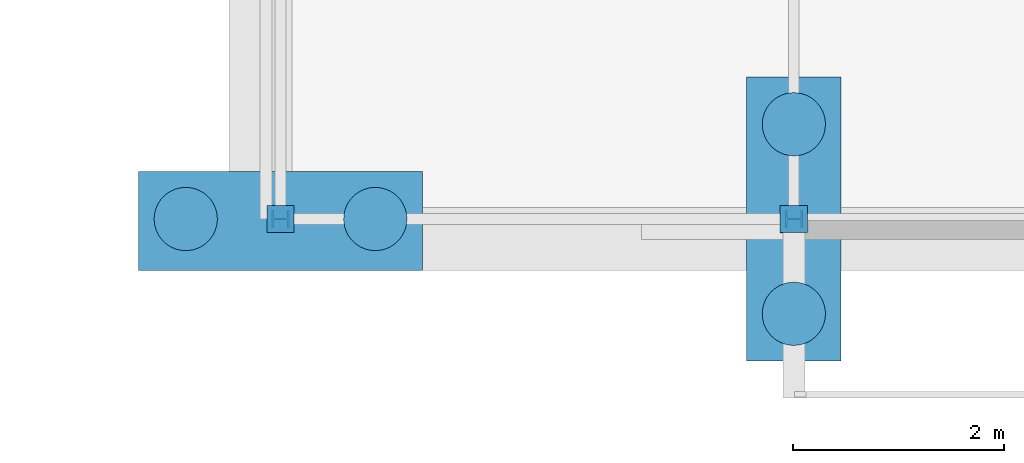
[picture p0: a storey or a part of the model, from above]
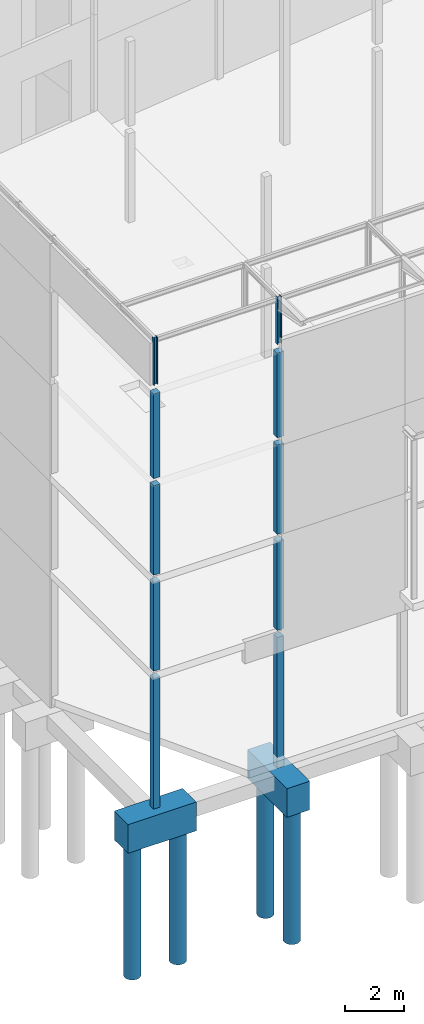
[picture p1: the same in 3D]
Properties of the parts of a building model (IFC2X3)

# File
Description: ViewDefinition[CoordinationView_V2.0]
File name: Struc.ifc
Time: 2015-04-22T10:52:00
Author: TEKLAAD\alco
Organization: Structural Designer
Written by: IFC Database Version:Work
Made in: Tekla Structures 21.0, IFC Export Version: 4.0.0.0 Mar 10 2015

# IfcSite, Undefined
RefElevation: 0 mm

# IfcBuildingStorey, Undefined
In: Undefined
Elevation: 0 mm

# IfcBeam: 1200*1000 (3)
In: Undefined
Description: 1200*1000; Material: CONCRETE/C30/37
Tekla Commun - Etage d'implantation: Fondation; Phase: 102; Classe: 4; Matériau: C30/37; Profil: 1200*1000; Nom: LONGRINE
Pset_BeamCommon - LoadBearing: yes
Name | Repère de pièce = Reference | Repère d'assemblage
2 x LONGRINE | Béton_SO-15 | SO11
LONGRINE | LO40 | LO40

# IfcBeam: 1200*900 (4)
In: Undefined
Description: 1200*900; Material: CONCRETE/C30/37
Tekla Commun - Etage d'implantation: Fondation; Phase: 102; Classe: 4; Matériau: C30/37; Profil: 1200*900; Nom: LONGRINE
Pset_BeamCommon - LoadBearing: yes
Name | Repère de pièce = Reference | Repère d'assemblage
2 x LONGRINE | Béton_SO-14 | SO11
LONGRINE | LO39 | LO39
LONGRINE | LO38 | LO38

# IfcBeam: 600*200, LONGRINE
In: Undefined
Description: 600*200; Material: CONCRETE/C30/37
Tekla Commun - Etage d'implantation: Fondation; Repère de pièce: LO41; Repère d'assemblage: LO41; Phase: 102; Classe: 4; Matériau: C30/37; Profil: 600*200; Nom: LONGRINE
Pset_BeamCommon - LoadBearing: yes; Reference: LO41

# IfcBeam: 600*400 (4)
In: Undefined
Description: 600*400; Material: CONCRETE/C30/37
Tekla Commun - Etage d'implantation: Fondation; Phase: 102; Classe: 4; Matériau: C30/37; Profil: 600*400; Nom: LONGRINE
Pset_BeamCommon - LoadBearing: yes
Name | Repère de pièce = Repère d'assemblage = Reference
LONGRINE | LO42
LONGRINE | LO43
2 x LONGRINE | LO44

# IfcBeam: 600*600 (49)
In: Undefined
Description: 600*600; Material: CONCRETE/C30/37
Tekla Commun - Etage d'implantation: Fondation; Phase: 102; Classe: 4; Matériau: C30/37; Profil: 600*600; Nom: LONGRINE
Pset_BeamCommon - LoadBearing: yes
Name | Repère de pièce = Repère d'assemblage = Reference
2 x LONGRINE | LO36
LONGRINE | LO37
2 x LONGRINE | LO32
2 x LONGRINE | LO35
2 x LONGRINE | LO34
LONGRINE | LO33
LONGRINE | LO31
2 x LONGRINE | LO26
LONGRINE | LO28
LONGRINE | LO27
LONGRINE | LO25
LONGRINE | LO24
LONGRINE | LO23
LONGRINE | LO22
LONGRINE | LO21
LONGRINE | LO1
LONGRINE | LO2
LONGRINE | LO19
LONGRINE | LO18
LONGRINE | LO17
LONGRINE | LO16
LONGRINE | LO15
LONGRINE | LO13
LONGRINE | LO12
LONGRINE | LO11
LONGRINE | LO10
3 x LONGRINE | LO9
LONGRINE | LO8
LONGRINE | LO7
LONGRINE | LO6
9 x LONGRINE | LO4
2 x LONGRINE | LO5
LONGRINE | LO3

# IfcBeam: 600*800 (3)
In: Undefined
Description: 600*800; Material: CONCRETE/C30/37
Tekla Commun - Etage d'implantation: Fondation; Phase: 102; Classe: 4; Matériau: C30/37; Profil: 600*800; Nom: LONGRINE
Pset_BeamCommon - LoadBearing: yes
Name | Repère de pièce = Repère d'assemblage = Reference
LONGRINE | LO30
LONGRINE | LO29
LONGRINE | LO20

# IfcBeam: 850*600, LONGRINE
In: Undefined
Description: 850*600; Material: CONCRETE/C30/37
Tekla Commun - Etage d'implantation: Fondation; Repère de pièce: LO14; Repère d'assemblage: LO14; Phase: 102; Classe: 4; Matériau: C30/37; Profil: 850*600; Nom: LONGRINE
Pset_BeamCommon - LoadBearing: yes; Reference: LO14

# IfcBeam: HEB200 (10)
In: Undefined
Description: HEB200; Material: STEEL/S275JR
Tekla Commun - Phase: 701; Classe: 3; Matériau: S275JR; Profil: HEB200; Nom: POUTRE
Pset_BeamCommon - LoadBearing: yes
Name | Repère de pièce = Repère d'assemblage = Reference
POUTRE | PO76
POUTRE | PO75
POUTRE | PO74
POUTRE | PO73
POUTRE | PO72
POUTRE | PO71
POUTRE | PO70
POUTRE | PO69
POUTRE | PO68
POUTRE | PO67

# IfcBeam: IPE200 (107)
In: Undefined
Description: IPE200; Material: STEEL/S275JR
Tekla Commun - Phase: 702; Classe: 3; Matériau: S275JR; Profil: IPE200; Nom: POUTRE
Pset_BeamCommon - LoadBearing: yes
Name | Repère de pièce = Repère d'assemblage = Reference
6 x POUTRE | PO62
2 x POUTRE | PO66
4 x POUTRE | PO61
POUTRE | PO65
2 x POUTRE | PO64
POUTRE | PO63
POUTRE | PO28
POUTRE | PO60
POUTRE | PO59
POUTRE | PO58
6 x POUTRE | PO40
POUTRE | PO57
4 x POUTRE | PO52
POUTRE | PO56
2 x POUTRE | PO55
POUTRE | PO54
POUTRE | PO53
21 x POUTRE | PO41
POUTRE | PO26
POUTRE | PO25
POUTRE | PO51
2 x POUTRE | PO49
POUTRE | PO50
POUTRE | PO48
POUTRE | PO47
POUTRE | PO46
POUTRE | PO45
POUTRE | PO24
POUTRE | PO27
2 x POUTRE | PO44
20 x POUTRE | PO42
4 x POUTRE | PO43
POUTRE | PO39
POUTRE | PO38
POUTRE | PO37
POUTRE | PO36
POUTRE | PO35
POUTRE | PO34
2 x POUTRE | PO33
POUTRE | PO32
POUTRE | PO31
POUTRE | PO30
POUTRE | PO29

# IfcBeam: IPE300, POUTRE
In: Undefined
Description: IPE300; Material: STEEL/S275JR
Tekla Commun - Repère de pièce: PO1; Repère d'assemblage: PO1; Phase: 702; Classe: 3; Matériau: S275JR; Profil: IPE300; Nom: POUTRE
Pset_BeamCommon - LoadBearing: yes; Reference: PO1

# IfcBeam: IPE400 (6)
In: Undefined
Description: IPE400; Material: STEEL/S275JR
Tekla Commun - Phase: 702; Classe: 3; Matériau: S275JR; Profil: IPE400; Nom: POUTRE
Pset_BeamCommon - LoadBearing: yes
Name | Repère de pièce = Repère d'assemblage = Reference
POUTRE | PO7
POUTRE | PO6
POUTRE | PO3
POUTRE | PO5
POUTRE | PO2
POUTRE | PO4

# IfcBeam: PHI533-200-10-14*210-14*210 (23)
In: Undefined
Description: PHI533-200-10-14*210-14*210; Material: STEEL/S275JR
Tekla Commun - Phase: 702; Classe: 3; Matériau: S275JR; Profil: PHI533-200-10-14*210-14*210; Nom: POUTRE
Pset_BeamCommon - LoadBearing: yes
Name | Repère de pièce = Repère d'assemblage = Reference
20 x POUTRE | PO11
POUTRE | PO10
POUTRE | PO9
POUTRE | PO8

# IfcBeam: UPE120 (24)
In: Undefined
Description: UPE120; Material: STEEL/S275JR
Tekla Commun - Classe: 3; Matériau: S275JR; Profil: UPE120; Nom: POUTRE
Pset_BeamCommon - LoadBearing: yes
Name | Repère de pièce = Repère d'assemblage = Reference | Phase
2 x POUTRE | PO22 | 702
POUTRE | PO15 | 702
POUTRE | PO23 | 702
POUTRE | PO14 | 702
3 x POUTRE | PO20 | 702
POUTRE | PO13 | 702
POUTRE | PO21 | 702
POUTRE | PO12 | 702
POUTRE | PO19 | 601
POUTRE | PO18 | 702
9 x POUTRE | PO16 | 702
2 x POUTRE | PO17 | 702

# IfcBeam: UPE200 (18)
In: Undefined
Description: UPE200; Material: STEEL/S275JR
Tekla Commun - Phase: 701; Classe: 3; Matériau: S275JR; Profil: UPE200; Nom: POUTRE
Pset_BeamCommon - LoadBearing: yes
Name | Repère de pièce = Repère d'assemblage = Reference
2 x POUTRE | PO81
7 x POUTRE | PO80
2 x POUTRE | PO78
7 x POUTRE | PO77

# IfcColumn: 1200*1200 (4)
In: Undefined
Description: 1200*1200; Material: CONCRETE/C30/37
Tekla Commun - Etage d'implantation: Fondation; Repère de pièce: SO9; Repère d'assemblage: SO9; Phase: 102; Classe: 4; Matériau: C30/37; Profil: 1200*1200; Nom: SEMELLE
Pset_ColumnCommon - LoadBearing: yes; Reference: SO9

# IfcColumn: 1200*1350 (2)
In: Undefined
Description: 1200*1350; Material: CONCRETE/C30/37
Tekla Commun - Etage d'implantation: Fondation; Repère de pièce: Béton_SO-113; Repère d'assemblage: SO11; Phase: 102; Classe: 4; Matériau: C30/37; Profil: 1200*1350; Nom: SEMELLE
Pset_ColumnCommon - LoadBearing: yes; Reference: Béton_SO-113

# IfcColumn: 1200*2459, SEMELLE
In: Undefined
Description: 1200*2459; Material: CONCRETE/C30/37
Tekla Commun - Etage d'implantation: Fondation; Repère de pièce: SO8; Repère d'assemblage: SO8; Phase: 102; Classe: 4; Matériau: C30/37; Profil: 1200*2459; Nom: SEMELLE
Pset_ColumnCommon - LoadBearing: yes; Reference: SO8

# IfcColumn: 1200*2460 (7)
In: Undefined
Description: 1200*2460; Material: CONCRETE/C30/37
Tekla Commun - Etage d'implantation: Fondation; Phase: 102; Classe: 4; Matériau: C30/37; Profil: 1200*2460; Nom: SEMELLE
Pset_ColumnCommon - LoadBearing: yes
Name | Repère de pièce = Repère d'assemblage = Reference
6 x SEMELLE | SO7
SEMELLE | SO7(?)

# IfcColumn: 1200*2700, SEMELLE
In: Undefined
Description: 1200*2700; Material: CONCRETE/C30/37
Tekla Commun - Etage d'implantation: Fondation; Repère de pièce: SO13; Repère d'assemblage: SO13; Phase: 102; Classe: 4; Matériau: C30/37; Profil: 1200*2700; Nom: SEMELLE
Pset_ColumnCommon - LoadBearing: yes; Reference: SO13

# IfcColumn: 1200*4695, SEMELLE
In: Undefined
Description: 1200*4695; Material: CONCRETE/C30/37
Tekla Commun - Etage d'implantation: Fondation; Repère de pièce: SO10; Repère d'assemblage: SO10; Phase: 102; Classe: 4; Matériau: C30/37; Profil: 1200*4695; Nom: SEMELLE
Pset_ColumnCommon - LoadBearing: yes; Reference: SO10

# IfcColumn: 1200*4775, SEMELLE
In: Undefined
Description: 1200*4775; Material: CONCRETE/C30/37
Tekla Commun - Etage d'implantation: Fondation; Repère de pièce: SO12; Repère d'assemblage: SO12; Phase: 102; Classe: 4; Matériau: C30/37; Profil: 1200*4775; Nom: SEMELLE
Pset_ColumnCommon - LoadBearing: yes; Reference: SO12

# IfcColumn: 1500*1500, SEMELLE
In: Undefined
Description: 1500*1500; Material: CONCRETE/C30/37
Tekla Commun - Etage d'implantation: Fondation; Repère de pièce: SO5; Repère d'assemblage: SO5; Phase: 102; Classe: 4; Matériau: C30/37; Profil: 1500*1500; Nom: SEMELLE
Pset_ColumnCommon - LoadBearing: yes; Reference: SO5

# IfcColumn: 260*260 (185)
In: Undefined
Description: 260*260; Material: CONCRETE/C25/30
Tekla Commun - Classe: 13; Matériau: C25/30; Profil: 260*260; Nom: POTEAU
Pset_ColumnCommon - LoadBearing: yes
Name | Etage d'implantation | Repère de pièce = Repère d'assemblage = Reference | Phase
49 x POTEAU | 3ème | Pt7 | 502
36 x POTEAU | 2ème | Pt11 | 402
36 x POTEAU | 1er | Pt4 | 302
47 x POTEAU | Rdc | Pt1 | 202
2 x POTEAU | 1er | Pt3 | 302
2 x POTEAU | 2ème | Pt10 | 402
11 x POTEAU | 2ème | Pt5 | 302
POTEAU | Rdc | Pt6 | 202
POTEAU | Rdc | Pt2 | 202

# IfcColumn: 2700*2700, SEMELLE
In: Undefined
Description: 2700*2700; Material: CONCRETE/C30/37
Tekla Commun - Etage d'implantation: Fondation; Repère de pièce: SO4; Repère d'assemblage: SO4; Phase: 102; Classe: 4; Matériau: C30/37; Profil: 2700*2700; Nom: SEMELLE
Pset_ColumnCommon - LoadBearing: yes; Reference: SO4

# IfcColumn: 2700*900 (32)
In: Undefined
Description: 2700*900; Material: CONCRETE/C30/37
Tekla Commun - Etage d'implantation: Fondation; Phase: 102; Classe: 4; Matériau: C30/37; Profil: 2700*900; Nom: SEMELLE
Pset_ColumnCommon - LoadBearing: yes
Name | Repère de pièce = Repère d'assemblage = Reference
31 x SEMELLE | SO2
SEMELLE | SO2(?)

# IfcColumn: 2700*940 (2)
In: Undefined
Description: 2700*940; Material: CONCRETE/C30/37
Tekla Commun - Etage d'implantation: Fondation; Repère de pièce: SO1; Repère d'assemblage: SO1; Phase: 102; Classe: 4; Matériau: C30/37; Profil: 2700*940; Nom: SEMELLE
Pset_ColumnCommon - LoadBearing: yes; Reference: SO1

# IfcColumn: 3000*1500, SEMELLE
In: Undefined
Description: 3000*1500; Material: CONCRETE/C30/37
Tekla Commun - Etage d'implantation: Fondation; Repère de pièce: SO6; Repère d'assemblage: SO6; Phase: 102; Classe: 4; Matériau: C30/37; Profil: 3000*1500; Nom: SEMELLE
Pset_ColumnCommon - LoadBearing: yes; Reference: SO6

# IfcColumn: 900*900 (8)
In: Undefined
Description: 900*900; Material: CONCRETE/C30/37
Tekla Commun - Etage d'implantation: Fondation; Phase: 102; Classe: 4; Matériau: C30/37; Profil: 900*900; Nom: SEMELLE
Pset_ColumnCommon - LoadBearing: yes
Name | Repère de pièce = Repère d'assemblage = Reference
7 x SEMELLE | SO3
SEMELLE | SO14

# IfcColumn: D500 (2)
In: Undefined
Description: D500; Material: CONCRETE/C25/30
Tekla Commun - Classe: 13; Matériau: C25/30; Profil: D500; Nom: POTEAU
Pset_ColumnCommon - LoadBearing: yes
Name | Etage d'implantation | Repère de pièce = Repère d'assemblage = Reference | Phase
POTEAU | 2ème | Pt9 | 402
POTEAU | Rdc | Pt8 | 202

# IfcColumn: D600 (135)
In: Undefined
Description: D600; Material: CONCRETE/C25/30
Tekla Commun - Etage d'implantation: Fondation; Phase: 101; Classe: 13; Matériau: C25/30; Profil: D600; Nom: PIEU
Pset_ColumnCommon - LoadBearing: yes
Name | Repère de pièce = Repère d'assemblage = Reference
62 x PIEU | PI1
11 x PIEU | PI4
55 x PIEU | PI2
PIEU | PI3
2 x PIEU | PI2(?)
4 x PIEU | PI5

# IfcColumn: HEB160 (84)
In: Undefined
Description: HEB160; Material: STEEL/S275JR
Tekla Commun - Phase: 702; Classe: 6; Matériau: S275JR; Profil: HEB160; Nom: POTEAU
Pset_ColumnCommon - LoadBearing: yes
Name | Repère de pièce = Repère d'assemblage = Reference
75 x POTEAU | PT1
9 x POTEAU | PT2

# IfcColumn: UPE200 (10)
In: Undefined
Description: UPE200; Material: STEEL/S275JR
Tekla Commun - Repère de pièce: PO79; Repère d'assemblage: PO79; Phase: 701; Classe: 3; Matériau: S275JR; Profil: UPE200; Nom: POUTRE
Pset_ColumnCommon - LoadBearing: yes; Reference: PO79

# IfcSlab: 150*8179, DALLE
In: Undefined
Description: 150*8179; PredefinedType: FLOOR; Material: CONCRETE/C25/30 150 mm
Tekla Commun - Etage d'implantation: 4ème; Repère de pièce: DA1; Repère d'assemblage: DA1; Phase: 601; Classe: 5; Matériau: C25/30; Profil: 150*8179; Nom: DALLE
Pset_SlabCommon - LoadBearing: yes; Reference: DA1

# IfcSlab: 230*1916, PALIER
In: Undefined
Description: 230*1916; PredefinedType: FLOOR; Material: CONCRETE/C30/37 230 mm
Tekla Commun - Etage d'implantation: Rdc; Repère de pièce: PAL2; Repère d'assemblage: PAL2; Phase: 201; Classe: 11; Matériau: C30/37; Profil: 230*1916; Nom: PALIER
Pset_SlabCommon - LoadBearing: yes; Reference: PAL2

# IfcSlab: 300*1020 (4)
In: Undefined
Description: 300*1020; PredefinedType: FLOOR; Material: CONCRETE/C30/37 300 mm
Tekla Commun - Repère de pièce: DA16; Repère d'assemblage: DA16; Classe: 8; Matériau: C30/37; Profil: 300*1020; Nom: DALLE
Pset_SlabCommon - LoadBearing: yes; Reference: DA16
Name | Etage d'implantation | Phase
DALLE | 3ème | 501
DALLE | 2ème | 401
DALLE | 1er | 301
DALLE | Rdc | 201

# IfcSlab: 300*1251 (4)
In: Undefined
Description: 300*1251; PredefinedType: FLOOR; Material: CONCRETE/C30/37 300 mm
Tekla Commun - Classe: 8; Matériau: C30/37; Profil: 300*1251; Nom: DALLE
Pset_SlabCommon - LoadBearing: yes
Name | Etage d'implantation | Repère de pièce = Repère d'assemblage = Reference | Phase
DALLE | 3ème | DA25 | 501
DALLE | 2ème | DA25 | 401
DALLE | 1er | DA25 | 301
DALLE | Rdc | DA21 | 201

# IfcSlab: 300*1325 (4)
In: Undefined
Description: 300*1325; PredefinedType: FLOOR; Material: CONCRETE/C30/37 300 mm
Tekla Commun - Classe: 8; Matériau: C30/37; Profil: 300*1325; Nom: DALLE
Pset_SlabCommon - LoadBearing: yes
Name | Etage d'implantation | Repère de pièce = Repère d'assemblage = Reference | Phase
DALLE | 3ème | DA24 | 501
DALLE | 2ème | DA24 | 401
DALLE | 1er | DA24 | 301
DALLE | Rdc | DA22 | 201

# IfcSlab: 300*1374 (4)
In: Undefined
Description: 300*1374; PredefinedType: FLOOR; Material: CONCRETE/C30/37 300 mm
Tekla Commun - Repère de pièce: DA15; Repère d'assemblage: DA15; Classe: 8; Matériau: C30/37; Profil: 300*1374; Nom: DALLE
Pset_SlabCommon - LoadBearing: yes; Reference: DA15
Name | Etage d'implantation | Phase
DALLE | 3ème | 501
DALLE | 2ème | 401
DALLE | 1er | 301
DALLE | Rdc | 201

# IfcSlab: 300*13791, DALLE
In: Undefined
Description: 300*13791; PredefinedType: FLOOR; Material: CONCRETE/C30/37 300 mm
Tekla Commun - Etage d'implantation: 2ème; Repère de pièce: DA31; Repère d'assemblage: DA31; Phase: 401; Classe: 8; Matériau: C30/37; Profil: 300*13791; Nom: DALLE
Pset_SlabCommon - LoadBearing: yes; Reference: DA31

# IfcSlab: 300*1430 (8)
In: Undefined
Description: 300*1430; PredefinedType: FLOOR; Material: CONCRETE/C30/37 300 mm
Tekla Commun - Classe: 8; Matériau: C30/37; Profil: 300*1430; Nom: DALLE
Pset_SlabCommon - LoadBearing: yes
Name | Etage d'implantation | Repère de pièce = Repère d'assemblage = Reference | Phase
DALLE | 3ème | DA18 | 501
DALLE | 3ème | DA17 | 501
DALLE | 2ème | DA18 | 401
DALLE | 2ème | DA17 | 401
DALLE | 1er | DA18 | 301
DALLE | 1er | DA17 | 301
DALLE | Rdc | DA18 | 201
DALLE | Rdc | DA17 | 201

# IfcSlab: 300*1578, DALLE
In: Undefined
Description: 300*1578; PredefinedType: FLOOR; Material: CONCRETE/C30/37 300 mm
Tekla Commun - Etage d'implantation: Rdc; Repère de pièce: DA3; Repère d'assemblage: DA3; Phase: 201; Classe: 8; Matériau: C30/37; Profil: 300*1578; Nom: DALLE
Pset_SlabCommon - LoadBearing: yes; Reference: DA3

# IfcSlab: 300*1604 (4)
In: Undefined
Description: 300*1604; PredefinedType: FLOOR; Material: CONCRETE/C30/37 300 mm
Tekla Commun - Repère de pièce: DA14; Repère d'assemblage: DA14; Classe: 8; Matériau: C30/37; Profil: 300*1604; Nom: DALLE
Pset_SlabCommon - LoadBearing: yes; Reference: DA14
Name | Etage d'implantation | Phase
DALLE | 3ème | 501
DALLE | 2ème | 401
DALLE | 1er | 301
DALLE | Rdc | 201

# IfcSlab: 300*1683, DALLE
In: Undefined
Description: 300*1683; PredefinedType: FLOOR; Material: CONCRETE/C30/37 300 mm
Tekla Commun - Etage d'implantation: 3ème; Repère de pièce: DA20; Repère d'assemblage: DA20; Phase: 501; Classe: 8; Matériau: C30/37; Profil: 300*1683; Nom: DALLE
Pset_SlabCommon - LoadBearing: yes; Reference: DA20

# IfcSlab: 300*1866 (4)
In: Undefined
Description: 300*1866; PredefinedType: FLOOR; Material: CONCRETE/C30/37 300 mm
Tekla Commun - Repère de pièce: DA12; Repère d'assemblage: DA12; Classe: 8; Matériau: C30/37; Profil: 300*1866; Nom: DALLE
Pset_SlabCommon - LoadBearing: yes; Reference: DA12
Name | Etage d'implantation | Phase
DALLE | 3ème | 501
DALLE | 2ème | 401
DALLE | 1er | 301
DALLE | Rdc | 201

# IfcSlab: 300*1875 (4)
In: Undefined
Description: 300*1875; PredefinedType: FLOOR; Material: CONCRETE/C30/37 300 mm
Tekla Commun - Repère de pièce: DA13; Repère d'assemblage: DA13; Classe: 8; Matériau: C30/37; Profil: 300*1875; Nom: DALLE
Pset_SlabCommon - LoadBearing: yes; Reference: DA13
Name | Etage d'implantation | Phase
DALLE | 3ème | 501
DALLE | 2ème | 401
DALLE | 1er | 301
DALLE | Rdc | 201

# IfcSlab: 300*2145 (2)
In: Undefined
Description: 300*2145; PredefinedType: FLOOR; Material: CONCRETE/C30/37 300 mm
Tekla Commun - Etage d'implantation: Rdc; Phase: 201; Classe: 8; Matériau: C30/37; Profil: 300*2145; Nom: DALLE
Pset_SlabCommon - LoadBearing: yes
Name | Repère de pièce = Repère d'assemblage = Reference
DALLE | DA9
DALLE | DA8

# IfcSlab: 300*2425, DALLE
In: Undefined
Description: 300*2425; PredefinedType: FLOOR; Material: CONCRETE/C30/37 300 mm
Tekla Commun - Etage d'implantation: Rdc; Repère de pièce: DA10; Repère d'assemblage: DA10; Phase: 201; Classe: 8; Matériau: C30/37; Profil: 300*2425; Nom: DALLE
Pset_SlabCommon - LoadBearing: yes; Reference: DA10

# IfcSlab: 300*2445 (2)
In: Undefined
Description: 300*2445; PredefinedType: FLOOR; Material: CONCRETE/C30/37 300 mm
Tekla Commun - Etage d'implantation: 4ème; Phase: 601; Classe: 8; Matériau: C30/37; Profil: 300*2445; Nom: DALLE
Pset_SlabCommon - LoadBearing: yes
Name | Repère de pièce = Repère d'assemblage = Reference
DALLE | A2
DALLE | A1

# IfcSlab: 300*2625 (3)
In: Undefined
Description: 300*2625; PredefinedType: FLOOR; Material: CONCRETE/C30/37 300 mm
Tekla Commun - Classe: 8; Matériau: C30/37; Profil: 300*2625; Nom: DALLE
Pset_SlabCommon - LoadBearing: yes
Name | Etage d'implantation | Repère de pièce = Repère d'assemblage = Reference | Phase
DALLE | 2ème | DA28 | 401
DALLE | 1er | DA27 | 301
DALLE | Rdc | DA11 | 201

# IfcSlab: 300*2640, DALLE
In: Undefined
Description: 300*2640; PredefinedType: FLOOR; Material: CONCRETE/C30/37 300 mm
Tekla Commun - Etage d'implantation: Rdc; Repère de pièce: DA26; Repère d'assemblage: DA26; Phase: 201; Classe: 8; Matériau: C30/37; Profil: 300*2640; Nom: DALLE
Pset_SlabCommon - LoadBearing: yes; Reference: DA26

# IfcSlab: 300*27379, DALLE
In: Undefined
Description: 300*27379; PredefinedType: FLOOR; Material: CONCRETE/C30/37 300 mm
Tekla Commun - Etage d'implantation: Rdc; Repère de pièce: DA4; Repère d'assemblage: DA4; Phase: 201; Classe: 8; Matériau: C30/37; Profil: 300*27379; Nom: DALLE
Pset_SlabCommon - LoadBearing: yes; Reference: DA4

# IfcSlab: 300*30937, DALLE
In: Undefined
Description: 300*30937; PredefinedType: FLOOR; Material: CONCRETE/C30/37 300 mm
Tekla Commun - Etage d'implantation: 4ème; Repère de pièce: DA29; Repère d'assemblage: DA29; Phase: 601; Classe: 8; Matériau: C30/37; Profil: 300*30937; Nom: DALLE
Pset_SlabCommon - LoadBearing: yes; Reference: DA29

# IfcSlab: 300*30960, DALLE
In: Undefined
Description: 300*30960; PredefinedType: FLOOR; Material: CONCRETE/C30/37 300 mm
Tekla Commun - Etage d'implantation: 3ème; Repère de pièce: DA30; Repère d'assemblage: DA30; Phase: 501; Classe: 8; Matériau: C30/37; Profil: 300*30960; Nom: DALLE
Pset_SlabCommon - LoadBearing: yes; Reference: DA30

# IfcSlab: 300*3100, DALLE
In: Undefined
Description: 300*3100; PredefinedType: FLOOR; Material: CONCRETE/C30/37 300 mm
Tekla Commun - Etage d'implantation: Rdc; Repère de pièce: DA7; Repère d'assemblage: DA7; Phase: 201; Classe: 8; Matériau: C30/37; Profil: 300*3100; Nom: DALLE
Pset_SlabCommon - LoadBearing: yes; Reference: DA7

# IfcSlab: 300*31019, DALLE
In: Undefined
Description: 300*31019; PredefinedType: FLOOR; Material: CONCRETE/C30/37 300 mm
Tekla Commun - Etage d'implantation: Rdc; Repère de pièce: DA2; Repère d'assemblage: DA2; Phase: 201; Classe: 8; Matériau: C30/37; Profil: 300*31019; Nom: DALLE
Pset_SlabCommon - LoadBearing: yes; Reference: DA2

# IfcSlab: 300*3400, DALLE
In: Undefined
Description: 300*3400; PredefinedType: FLOOR; Material: CONCRETE/C30/37 300 mm
Tekla Commun - Etage d'implantation: 4ème; Repère de pièce: DA19; Repère d'assemblage: DA19; Phase: 601; Classe: 8; Matériau: C30/37; Profil: 300*3400; Nom: DALLE
Pset_SlabCommon - LoadBearing: yes; Reference: DA19

# IfcSlab: 300*350, DALLE
In: Undefined
Description: 300*350; PredefinedType: FLOOR; Material: CONCRETE/C30/37 300 mm
Tekla Commun - Etage d'implantation: Rdc; Repère de pièce: DA23; Repère d'assemblage: DA23; Phase: 201; Classe: 8; Matériau: C30/37; Profil: 300*350; Nom: DALLE
Pset_SlabCommon - LoadBearing: yes; Reference: DA23

# IfcSlab: 300*35828, DALLE
In: Undefined
Description: 300*35828; PredefinedType: FLOOR; Material: CONCRETE/C30/37 300 mm
Tekla Commun - Etage d'implantation: 2ème; Repère de pièce: DA32; Repère d'assemblage: DA32; Phase: 401; Classe: 8; Matériau: C30/37; Profil: 300*35828; Nom: DALLE
Pset_SlabCommon - LoadBearing: yes; Reference: DA32

# IfcSlab: 300*35838, DALLE
In: Undefined
Description: 300*35838; PredefinedType: FLOOR; Material: CONCRETE/C30/37 300 mm
Tekla Commun - Etage d'implantation: 1er; Repère de pièce: DA5; Repère d'assemblage: DA5; Phase: 301; Classe: 8; Matériau: C30/37; Profil: 300*35838; Nom: DALLE
Pset_SlabCommon - LoadBearing: yes; Reference: DA5

# IfcSlab: 300*3929, DALLE
In: Undefined
Description: 300*3929; PredefinedType: FLOOR; Material: CONCRETE/C30/37 300 mm
Tekla Commun - Etage d'implantation: 4ème; Repère de pièce: DA33; Repère d'assemblage: DA33; Phase: 601; Classe: 8; Matériau: C30/37; Profil: 300*3929; Nom: DALLE
Pset_SlabCommon - LoadBearing: yes; Reference: DA33

# IfcSlab: 300*3944, DALLE
In: Undefined
Description: 300*3944; PredefinedType: FLOOR; Material: CONCRETE/C30/37 300 mm
Tekla Commun - Etage d'implantation: Rdc; Repère de pièce: DA6; Repère d'assemblage: DA6; Phase: 201; Classe: 8; Matériau: C30/37; Profil: 300*3944; Nom: DALLE
Pset_SlabCommon - LoadBearing: yes; Reference: DA6

# IfcWall: 2071*115 (9)
In: Undefined
Description: 2071*115; Material: CONCRETE/C25/30
Tekla Commun - Etage d'implantation: 4ème; Phase: 602; Classe: 1; Matériau: C25/30; Profil: 2071*115; Nom: PANNEAU_FACADE
Pset_WallCommon - LoadBearing: yes
Name | Repère de pièce = Repère d'assemblage = Reference
PANNEAU_FACADE | PA25
PANNEAU_FACADE | PA24
PANNEAU_FACADE | PA23
PANNEAU_FACADE | PA22
PANNEAU_FACADE | PA21
PANNEAU_FACADE | PA20
PANNEAU_FACADE | PA19
PANNEAU_FACADE | PA18
PANNEAU_FACADE | PA71

# IfcWall: 3061*150 (2)
In: Undefined
Description: 3061*150; Material: CONCRETE/C25/30
Tekla Commun - Etage d'implantation: 4ème; Phase: 602; Classe: 3; Matériau: C25/30; Profil: 3061*150; Nom: VOILE_15CM
Pset_WallCommon - LoadBearing: yes
Name | Repère de pièce = Repère d'assemblage = Reference
VOILE_15CM | VO51
VOILE_15CM | VO50

# IfcWall: 3830*150 (3)
In: Undefined
Description: 3830*150
Tekla Commun - Etage d'implantation: 3ème; Phase: 502; Profil: 3830*150
Pset_WallCommon - LoadBearing: yes
Name | Material | Repère de pièce = Repère d'assemblage = Reference | Classe | Matériau | Nom
MACONNERIE_15CM | CONCRETE/BRIQUE | MA28 | 10 | BRIQUE | MACONNERIE_15CM
VOILE_15CM | CONCRETE/C25/30 | VO41 | 3 | C25/30 | VOILE_15CM
VOILE_15CM | CONCRETE/C25/30 | VO40 | 3 | C25/30 | VOILE_15CM

# IfcWall: 3830*180 (9)
In: Undefined
Description: 3830*180; Material: CONCRETE/C25/30
Tekla Commun - Etage d'implantation: 3ème; Phase: 502; Classe: 1; Matériau: C25/30; Profil: 3830*180; Nom: PANNEAU_FACADE
Pset_WallCommon - LoadBearing: yes
Name | Repère de pièce = Repère d'assemblage = Reference
PANNEAU_FACADE | PA61
PANNEAU_FACADE | PA60
PANNEAU_FACADE | PA62
PANNEAU_FACADE | PA64
PANNEAU_FACADE | PA59
PANNEAU_FACADE | PA58
PANNEAU_FACADE | PA57
PANNEAU_FACADE | PA56
PANNEAU_FACADE | PA55

# IfcWall: 4005*150 (3)
In: Undefined
Description: 4005*150
Tekla Commun - Etage d'implantation: 1er; Phase: 302; Profil: 4005*150
Pset_WallCommon - LoadBearing: yes
Name | Material | Repère de pièce = Repère d'assemblage = Reference | Classe | Matériau | Nom
MACONNERIE_15CM | CONCRETE/BRIQUE | MA26 | 10 | BRIQUE | MACONNERIE_15CM
VOILE_15CM | CONCRETE/C25/30 | VO17 | 3 | C25/30 | VOILE_15CM
VOILE_15CM | CONCRETE/C25/30 | VO16 | 3 | C25/30 | VOILE_15CM

# IfcWall: 4005*180 (9)
In: Undefined
Description: 4005*180; Material: CONCRETE/C25/30
Tekla Commun - Etage d'implantation: 1er; Phase: 302; Classe: 1; Matériau: C25/30; Profil: 4005*180; Nom: PANNEAU_FACADE
Pset_WallCommon - LoadBearing: yes
Name | Repère de pièce = Repère d'assemblage = Reference
PANNEAU_FACADE | PA69
PANNEAU_FACADE | PA46
PANNEAU_FACADE | PA45
PANNEAU_FACADE | PA44
PANNEAU_FACADE | PA43
PANNEAU_FACADE | PA42
PANNEAU_FACADE | PA41
PANNEAU_FACADE | PA40
PANNEAU_FACADE | PA39

# IfcWall: 4025*150 (3)
In: Undefined
Description: 4025*150
Tekla Commun - Etage d'implantation: 2ème; Profil: 4025*150
Pset_WallCommon - LoadBearing: yes
Name | Material | Repère de pièce = Repère d'assemblage = Reference | Phase | Classe | Matériau | Nom
MACONNERIE_15CM | CONCRETE/BRIQUE | MA27 | 302 | 10 | BRIQUE | MACONNERIE_15CM
VOILE_15CM | CONCRETE/C25/30 | VO29 | 402 | 3 | C25/30 | VOILE_15CM
VOILE_15CM | CONCRETE/C25/30 | VO28 | 402 | 3 | C25/30 | VOILE_15CM

# IfcWall: 4025*180 (9)
In: Undefined
Description: 4025*180; Material: CONCRETE/C25/30
Tekla Commun - Etage d'implantation: 2ème; Phase: 402; Classe: 1; Matériau: C25/30; Profil: 4025*180; Nom: PANNEAU_FACADE
Pset_WallCommon - LoadBearing: yes
Name | Repère de pièce = Repère d'assemblage = Reference
PANNEAU_FACADE | PA70
PANNEAU_FACADE | PA54
PANNEAU_FACADE | PA53
PANNEAU_FACADE | PA52
PANNEAU_FACADE | PA51
PANNEAU_FACADE | PA50
PANNEAU_FACADE | PA49
PANNEAU_FACADE | PA48
PANNEAU_FACADE | PA47

# IfcWall: 4515*180, PANNEAU_FACADE
In: Undefined
Description: 4515*180; Material: CONCRETE/C25/30
Tekla Commun - Etage d'implantation: 4ème; Repère de pièce: PA6; Repère d'assemblage: PA6; Phase: 602; Classe: 1; Matériau: C25/30; Profil: 4515*180; Nom: PANNEAU_FACADE
Pset_WallCommon - LoadBearing: yes; Reference: PA6

# IfcWall: 4900*50 (6)
In: Undefined
Description: 4900*50; Material: STEEL/Steel_Undefined
Tekla Commun - Phase: 602; Classe: 12; Matériau: Steel_Undefined; Profil: 4900*50; Nom: HABILLAGE
Pset_WallCommon - LoadBearing: yes
Name | Repère de pièce = Repère d'assemblage = Reference
HABILLAGE | PA32
HABILLAGE | PA30
HABILLAGE | PA29
HABILLAGE | PA28
HABILLAGE | PA27
HABILLAGE | PA26

# IfcWall: 5000*150 (23)
In: Undefined
Description: 5000*150; Material: CONCRETE/BRIQUE
Tekla Commun - Etage d'implantation: Rdc; Phase: 202; Classe: 10; Matériau: BRIQUE; Profil: 5000*150; Nom: MACONNERIE_15CM
Pset_WallCommon - LoadBearing: yes
Name | Repère de pièce = Repère d'assemblage = Reference
MACONNERIE_15CM | MA25
MACONNERIE_15CM | MA15
MACONNERIE_15CM | MA24
MACONNERIE_15CM | MA12
MACONNERIE_15CM | MA11
MACONNERIE_15CM | MA10
MACONNERIE_15CM | MA9
MACONNERIE_15CM | MA23
MACONNERIE_15CM | MA22
MACONNERIE_15CM | MA7
MACONNERIE_15CM | MA14
MACONNERIE_15CM | MA6
MACONNERIE_15CM | MA5
MACONNERIE_15CM | MA21
MACONNERIE_15CM | MA20
MACONNERIE_15CM | MA3
MACONNERIE_15CM | MA2
MACONNERIE_15CM | MA19
MACONNERIE_15CM | MA18
MACONNERIE_15CM | MA13
MACONNERIE_15CM | MA17
MACONNERIE_15CM | MA16
MACONNERIE_15CM | MA1

# IfcWall: 5200*50, HABILLAGE
In: Undefined
Description: 5200*50; Material: STEEL/Steel_Undefined
Tekla Commun - Repère de pièce: PA31; Repère d'assemblage: PA31; Phase: 602; Classe: 12; Matériau: Steel_Undefined; Profil: 5200*50; Nom: HABILLAGE
Pset_WallCommon - LoadBearing: yes; Reference: PA31

# IfcWall: 5450*180 (11)
In: Undefined
Description: 5450*180; Material: CONCRETE/C25/30
Tekla Commun - Etage d'implantation: Rdc; Phase: 202; Classe: 1; Matériau: C25/30; Profil: 5450*180; Nom: PANNEAU_FACADE
Pset_WallCommon - LoadBearing: yes
Name | Repère de pièce = Repère d'assemblage = Reference
PANNEAU_FACADE | PA68
PANNEAU_FACADE | PA38
PANNEAU_FACADE | PA67
PANNEAU_FACADE | PA37
PANNEAU_FACADE | PA66
PANNEAU_FACADE | PA35
PANNEAU_FACADE | PA65
PANNEAU_FACADE | PA34
PANNEAU_FACADE | PA33
PANNEAU_FACADE | PA63
PANNEAU_FACADE | PA36

# IfcWall: 5750*150 (4)
In: Undefined
Description: 5750*150; Material: CONCRETE/C25/30
Tekla Commun - Etage d'implantation: Rdc; Phase: 202; Classe: 3; Matériau: C25/30; Profil: 5750*150; Nom: VOILE_15CM
Pset_WallCommon - LoadBearing: yes
Name | Repère de pièce = Repère d'assemblage = Reference
VOILE_15CM | VO15
VOILE_15CM | VO14
VOILE_15CM | VO4
VOILE_15CM | VO93

# IfcWallStandardCase: 1290*180, PANNEAU_FACADE
In: Undefined
Description: 1290*180; Material: CONCRETE/C25/30 180 mm
Tekla Commun - Etage d'implantation: 4ème; Repère de pièce: PA17; Repère d'assemblage: PA17; Phase: 602; Classe: 1; Matériau: C25/30; Profil: 1290*180; Nom: PANNEAU_FACADE
Pset_WallCommon - LoadBearing: yes; Reference: PA17

# IfcWallStandardCase: 1380*180 (9)
In: Undefined
Description: 1380*180; Material: CONCRETE/C25/30 180 mm
Tekla Commun - Etage d'implantation: 2ème; Phase: 402; Classe: 1; Matériau: C25/30; Profil: 1380*180; Nom: PANNEAU_FACADE
Pset_WallCommon - LoadBearing: yes
Name | Repère de pièce = Repère d'assemblage = Reference
6 x PANNEAU_FACADE | PA11
2 x PANNEAU_FACADE | PA12
PANNEAU_FACADE | PA2

# IfcWallStandardCase: 1771*115, PANNEAU_FACADE
In: Undefined
Description: 1771*115; Material: CONCRETE/C25/30 115 mm
Tekla Commun - Etage d'implantation: 4ème; Repère de pièce: PA72; Repère d'assemblage: PA72; Phase: 602; Classe: 1; Matériau: C25/30; Profil: 1771*115; Nom: PANNEAU_FACADE
Pset_WallCommon - LoadBearing: yes; Reference: PA72

# IfcWallStandardCase: 3061*150, VOILE_15CM
In: Undefined
Description: 3061*150; Material: CONCRETE/C25/30 150 mm
Tekla Commun - Etage d'implantation: 4ème; Repère de pièce: VO77; Repère d'assemblage: VO77; Phase: 602; Classe: 3; Matériau: C25/30; Profil: 3061*150; Nom: VOILE_15CM
Pset_WallCommon - LoadBearing: yes; Reference: VO77

# IfcWallStandardCase: 3530*100 (8)
In: Undefined
Description: 3530*100; Material: CONCRETE/C25/30 100 mm
Tekla Commun - Etage d'implantation: 3ème; Phase: 502; Classe: 3; Matériau: C25/30; Profil: 3530*100; Nom: VOILE_10CM
Pset_WallCommon - LoadBearing: yes
Name | Repère de pièce = Repère d'assemblage = Reference
VOILE_10CM | VO133
VOILE_10CM | VO131
VOILE_10CM | VO130
VOILE_10CM | VO129
VOILE_10CM | VO128
VOILE_10CM | VO126
VOILE_10CM | VO117
VOILE_10CM | VO116

# IfcWallStandardCase: 3530*150 (14)
In: Undefined
Description: 3530*150; Material: CONCRETE/C25/30 150 mm
Tekla Commun - Etage d'implantation: 3ème; Phase: 502; Matériau: C25/30; Profil: 3530*150; Nom: VOILE_15CM
Pset_WallCommon - LoadBearing: yes
Name | Repère de pièce = Repère d'assemblage = Reference | Classe
VOILE_15CM | VO76 | 3
VOILE_15CM | VO75 | 10
VOILE_15CM | VO48 | 3
VOILE_15CM | VO78 | 3
VOILE_15CM | VO47 | 3
VOILE_15CM | VO74 | 3
VOILE_15CM | VO82 | 3
VOILE_15CM | VO73 | 3
VOILE_15CM | VO72 | 3
VOILE_15CM | VO46 | 3
VOILE_15CM | VO88 | 3
VOILE_15CM | VO43 | 3
VOILE_15CM | VO71 | 3
VOILE_15CM | VO99 | 3

# IfcWallStandardCase: 3725*180 (2)
In: Undefined
Description: 3725*180; Material: CONCRETE/C25/30 180 mm
Tekla Commun - Etage d'implantation: 2ème; Phase: 402; Classe: 1; Matériau: C25/30; Profil: 3725*180; Nom: PANNEAU_FACADE
Pset_WallCommon - LoadBearing: yes
Name | Repère de pièce = Repère d'assemblage = Reference
PANNEAU_FACADE | PA13
PANNEAU_FACADE | PA5

# IfcWallStandardCase: 3830*150, VOILE_15CM
In: Undefined
Description: 3830*150; Material: CONCRETE/C25/30 150 mm
Tekla Commun - Etage d'implantation: 3ème; Repère de pièce: VO69; Repère d'assemblage: VO69; Phase: 502; Classe: 3; Matériau: C25/30; Profil: 3830*150; Nom: VOILE_15CM
Pset_WallCommon - LoadBearing: yes; Reference: VO69

# IfcWallStandardCase: 4005*100 (8)
In: Undefined
Description: 4005*100; Material: CONCRETE/C25/30 100 mm
Tekla Commun - Etage d'implantation: 1er; Phase: 302; Classe: 3; Matériau: C25/30; Profil: 4005*100; Nom: VOILE_10CM
Pset_WallCommon - LoadBearing: yes
Name | Repère de pièce = Repère d'assemblage = Reference
VOILE_10CM | VO113
VOILE_10CM | VO108
VOILE_10CM | VO107
VOILE_10CM | VO127
VOILE_10CM | VO110
VOILE_10CM | VO122
VOILE_10CM | VO121
VOILE_10CM | VO106

# IfcWallStandardCase: 4005*150 (25)
In: Undefined
Description: 4005*150; Material: CONCRETE/C25/30 150 mm
Tekla Commun - Etage d'implantation: 1er; Phase: 302; Matériau: C25/30; Profil: 4005*150; Nom: VOILE_15CM
Pset_WallCommon - LoadBearing: yes
Name | Repère de pièce = Repère d'assemblage = Reference | Classe
VOILE_15CM | VO61 | 3
VOILE_15CM | VO60 | 10
2 x VOILE_15CM | VO27 | 3
VOILE_15CM | VO26 | 3
VOILE_15CM | VO59 | 3
VOILE_15CM | VO101 | 3
VOILE_15CM | VO58 | 3
VOILE_15CM | VO25 | 3
VOILE_15CM | VO80 | 3
VOILE_15CM | VO86 | 3
VOILE_15CM | VO24 | 3
2 x VOILE_15CM | VO23 | 3
VOILE_15CM | VO22 | 3
VOILE_15CM | VO21 | 3
VOILE_15CM | VO20 | 3
VOILE_15CM | VO57 | 3
VOILE_15CM | VO95 | 3
VOILE_15CM | VO94 | 3
2 x VOILE_15CM | VO18 | 3
VOILE_15CM | VO19 | 3
VOILE_15CM | VO56 | 3
VOILE_15CM | VO55 | 3

# IfcWallStandardCase: 4025*100 (8)
In: Undefined
Description: 4025*100; Material: CONCRETE/C25/30 100 mm
Tekla Commun - Etage d'implantation: 2ème; Phase: 402; Classe: 3; Matériau: C25/30; Profil: 4025*100; Nom: VOILE_10CM
Pset_WallCommon - LoadBearing: yes
Name | Repère de pièce = Repère d'assemblage = Reference
VOILE_10CM | VO132
VOILE_10CM | VO115
VOILE_10CM | VO114
VOILE_10CM | VO112
VOILE_10CM | VO111
VOILE_10CM | VO125
VOILE_10CM | VO124
VOILE_10CM | VO123

# IfcWallStandardCase: 4025*150 (25)
In: Undefined
Description: 4025*150; Material: CONCRETE/C25/30 150 mm
Tekla Commun - Etage d'implantation: 2ème; Phase: 402; Matériau: C25/30; Profil: 4025*150; Nom: VOILE_15CM
Pset_WallCommon - LoadBearing: yes
Name | Repère de pièce = Repère d'assemblage = Reference | Classe
VOILE_15CM | VO68 | 3
VOILE_15CM | VO67 | 10
2 x VOILE_15CM | VO39 | 3
VOILE_15CM | VO38 | 3
VOILE_15CM | VO66 | 3
VOILE_15CM | VO98 | 3
VOILE_15CM | VO65 | 3
VOILE_15CM | VO37 | 3
VOILE_15CM | VO81 | 3
VOILE_15CM | VO87 | 3
VOILE_15CM | VO36 | 3
2 x VOILE_15CM | VO35 | 3
VOILE_15CM | VO34 | 3
VOILE_15CM | VO33 | 3
VOILE_15CM | VO32 | 3
VOILE_15CM | VO64 | 3
VOILE_15CM | VO97 | 3
VOILE_15CM | VO96 | 3
2 x VOILE_15CM | VO30 | 3
VOILE_15CM | VO31 | 3
VOILE_15CM | VO63 | 3
VOILE_15CM | VO62 | 3

# IfcWallStandardCase: 4025*180, PANNEAU_FACADE
In: Undefined
Description: 4025*180; Material: CONCRETE/C25/30 180 mm
Tekla Commun - Etage d'implantation: 2ème; Repère de pièce: PA10; Repère d'assemblage: PA10; Phase: 402; Classe: 1; Matériau: C25/30; Profil: 4025*180; Nom: PANNEAU_FACADE
Pset_WallCommon - LoadBearing: yes; Reference: PA10

# IfcWallStandardCase: 4370*180 (12)
In: Undefined
Description: 4370*180; Material: CONCRETE/C25/30 180 mm
Tekla Commun - Etage d'implantation: 3ème; Phase: 502; Classe: 1; Matériau: C25/30; Profil: 4370*180; Nom: PANNEAU_FACADE
Pset_WallCommon - LoadBearing: yes
Name | Repère de pièce = Repère d'assemblage = Reference
8 x PANNEAU_FACADE | PA15
PANNEAU_FACADE | PA1
2 x PANNEAU_FACADE | PA16
PANNEAU_FACADE | PA14

# IfcWallStandardCase: 4605*180, PANNEAU_FACADE
In: Undefined
Description: 4605*180; Material: CONCRETE/C25/30 180 mm
Tekla Commun - Etage d'implantation: 1er; Repère de pièce: PA7; Repère d'assemblage: PA7; Phase: 302; Classe: 1; Matériau: C25/30; Profil: 4605*180; Nom: PANNEAU_FACADE
Pset_WallCommon - LoadBearing: yes; Reference: PA7

# IfcWallStandardCase: 4700*150 (6)
In: Undefined
Description: 4700*150; Material: CONCRETE/C25/30 150 mm
Tekla Commun - Etage d'implantation: 3ème; Phase: 502; Classe: 3; Matériau: C25/30; Profil: 4700*150; Nom: VOILE_15CM
Pset_WallCommon - LoadBearing: yes
Name | Repère de pièce = Repère d'assemblage = Reference
VOILE_15CM | VO45
2 x VOILE_15CM | VO44
VOILE_15CM | VO90
VOILE_15CM | VO89
VOILE_15CM | VO100

# IfcWallStandardCase: 4905*180 (2)
In: Undefined
Description: 4905*180; Material: CONCRETE/C25/30 180 mm
Tekla Commun - Etage d'implantation: 1er; Phase: 302; Classe: 1; Matériau: C25/30; Profil: 4905*180; Nom: PANNEAU_FACADE
Pset_WallCommon - LoadBearing: yes
Name | Repère de pièce = Repère d'assemblage = Reference
PANNEAU_FACADE | PA4
PANNEAU_FACADE | PA3

# IfcWallStandardCase: 5000*150 (2)
In: Undefined
Description: 5000*150; Material: CONCRETE/BRIQUE 150 mm
Tekla Commun - Etage d'implantation: Rdc; Phase: 202; Classe: 10; Matériau: BRIQUE; Profil: 5000*150; Nom: MACONNERIE_15CM
Pset_WallCommon - LoadBearing: yes
Name | Repère de pièce = Repère d'assemblage = Reference
MACONNERIE_15CM | MA8
MACONNERIE_15CM | MA4

# IfcWallStandardCase: 5070*150 (4)
In: Undefined
Description: 5070*150; Material: CONCRETE/C25/30 150 mm
Tekla Commun - Etage d'implantation: 3ème; Phase: 502; Classe: 3; Matériau: C25/30; Profil: 5070*150; Nom: VOILE_15CM
Pset_WallCommon - LoadBearing: yes
Name | Repère de pièce = Repère d'assemblage = Reference
VOILE_15CM | VO49
2 x VOILE_15CM | VO42
VOILE_15CM | VO70

# IfcWallStandardCase: 5750*100 (8)
In: Undefined
Description: 5750*100; Material: CONCRETE/C25/30 100 mm
Tekla Commun - Etage d'implantation: Rdc; Phase: 202; Classe: 3; Matériau: C25/30; Profil: 5750*100; Nom: VOILE_10CM
Pset_WallCommon - LoadBearing: yes
Name | Repère de pièce = Repère d'assemblage = Reference
VOILE_10CM | VO120
VOILE_10CM | VO105
VOILE_10CM | VO104
VOILE_10CM | VO109
VOILE_10CM | VO119
VOILE_10CM | VO102
VOILE_10CM | VO103
VOILE_10CM | VO118

# IfcWallStandardCase: 5750*150 (10)
In: Undefined
Description: 5750*150; Material: CONCRETE/C25/30 150 mm
Tekla Commun - Etage d'implantation: Rdc; Phase: 202; Classe: 3; Matériau: C25/30; Profil: 5750*150; Nom: VOILE_15CM
Pset_WallCommon - LoadBearing: yes
Name | Repère de pièce = Repère d'assemblage = Reference
VOILE_15CM | VO85
VOILE_15CM | VO3
VOILE_15CM | VO84
VOILE_15CM | VO79
VOILE_15CM | VO83
VOILE_15CM | VO2
VOILE_15CM | VO8
VOILE_15CM | VO7
VOILE_15CM | VO1
VOILE_15CM | VO53

# IfcWallStandardCase: 600*180 (9)
In: Undefined
Description: 600*180; Material: CONCRETE/C25/30 180 mm
Tekla Commun - Etage d'implantation: 2ème; Phase: 302; Classe: 1; Matériau: C25/30; Profil: 600*180; Nom: PANNEAU_FACADE
Pset_WallCommon - LoadBearing: yes
Name | Repère de pièce = Repère d'assemblage = Reference
7 x PANNEAU_FACADE | PA8
2 x PANNEAU_FACADE | PA9

# IfcWallStandardCase: 6600*150 (13)
In: Undefined
Description: 6600*150; Material: CONCRETE/C25/30 150 mm
Tekla Commun - Etage d'implantation: Rdc; Phase: 202; Classe: 3; Matériau: C25/30; Profil: 6600*150; Nom: VOILE_15CM
Pset_WallCommon - LoadBearing: yes
Name | Repère de pièce = Repère d'assemblage = Reference
2 x VOILE_15CM | VO12
VOILE_15CM | VO13
2 x VOILE_15CM | VO11
VOILE_15CM | VO10
VOILE_15CM | VO54
VOILE_15CM | VO9
VOILE_15CM | VO6
VOILE_15CM | VO5
VOILE_15CM | VO52
VOILE_15CM | VO92
VOILE_15CM | VO91
